One B-rep face of a CAD part: STEP entity #7966.
In plain terms, the planar face has unit normal (0, 0, -1).
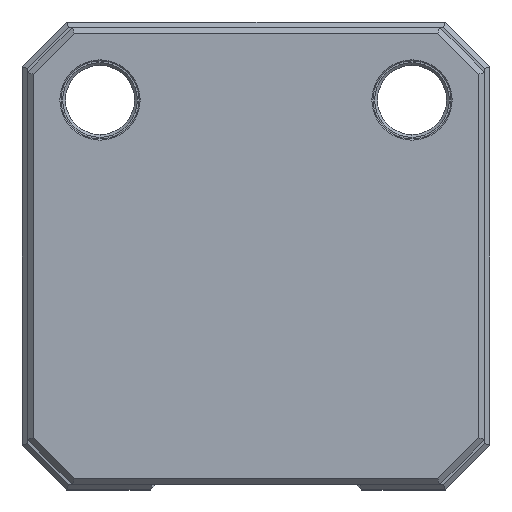
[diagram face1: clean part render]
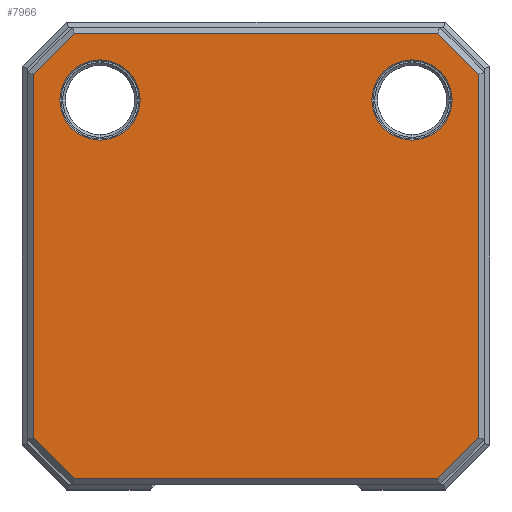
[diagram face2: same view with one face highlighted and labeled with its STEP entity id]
Its self-contained STEP definition (entity closure, numbers rounded to 3 decimals):
#1611 = EDGE_CURVE ( 'NONE', #13273, #13305, #17343, .T. ) ;
#1615 = EDGE_CURVE ( 'NONE', #13229, #13216, #7569, .T. ) ;
#1620 = EDGE_CURVE ( 'NONE', #13299, #13275, #17336, .T. ) ;
#1647 = EDGE_CURVE ( 'NONE', #13261, #13299, #17371, .T. ) ;
#1657 = EDGE_CURVE ( 'NONE', #13275, #13302, #17361, .T. ) ;
#1661 = EDGE_CURVE ( 'NONE', #13247, #13242, #7553, .T. ) ;
#1675 = EDGE_CURVE ( 'NONE', #13302, #13266, #17431, .T. ) ;
#1687 = EDGE_CURVE ( 'NONE', #13266, #13273, #17494, .T. ) ;
#1699 = EDGE_CURVE ( 'NONE', #13305, #13286, #17479, .T. ) ;
#1715 = EDGE_CURVE ( 'NONE', #13286, #13261, #17518, .T. ) ;
#1834 = EDGE_CURVE ( 'NONE', #13216, #13229, #7735, .T. ) ;
#1943 = EDGE_CURVE ( 'NONE', #13242, #13247, #7740, .T. ) ;
#4526 = AXIS2_PLACEMENT_3D ( 'NONE', #20304, #20255, #20301 ) ;
#6387 = EDGE_LOOP ( 'NONE', ( #19447, #19479 ) ) ;
#6462 = EDGE_LOOP ( 'NONE', ( #19484, #19480 ) ) ;
#6477 = EDGE_LOOP ( 'NONE', ( #19437, #19445, #19483, #19442, #19412, #19434, #19478, #19435 ) ) ;
#7536 = VECTOR ( 'NONE', #17348, 1000. ) ;
#7551 = AXIS2_PLACEMENT_3D ( 'NONE', #17341, #17324, #17302 ) ;
#7553 = CIRCLE ( 'NONE', #7590, 3.6 ) ;
#7559 = VECTOR ( 'NONE', #17478, 1000. ) ;
#7566 = VECTOR ( 'NONE', #17327, 1000. ) ;
#7567 = VECTOR ( 'NONE', #17393, 1000. ) ;
#7569 = CIRCLE ( 'NONE', #7551, 3.6 ) ;
#7587 = VECTOR ( 'NONE', #17413, 1000. ) ;
#7590 = AXIS2_PLACEMENT_3D ( 'NONE', #17448, #17414, #17443 ) ;
#7606 = VECTOR ( 'NONE', #17433, 1000. ) ;
#7643 = VECTOR ( 'NONE', #17539, 1000. ) ;
#7657 = VECTOR ( 'NONE', #17481, 1000. ) ;
#7680 = AXIS2_PLACEMENT_3D ( 'NONE', #17650, #17654, #17672 ) ;
#7735 = CIRCLE ( 'NONE', #7680, 3.6 ) ;
#7740 = CIRCLE ( 'NONE', #7769, 3.6 ) ;
#7769 = AXIS2_PLACEMENT_3D ( 'NONE', #16728, #16719, #16741 ) ;
#7966 = ADVANCED_FACE ( 'NONE', ( #20253, #20298, #20254 ), #20291, .F. ) ;
#13216 = VERTEX_POINT ( 'NONE', #20328 ) ;
#13229 = VERTEX_POINT ( 'NONE', #20346 ) ;
#13242 = VERTEX_POINT ( 'NONE', #20331 ) ;
#13247 = VERTEX_POINT ( 'NONE', #20313 ) ;
#13261 = VERTEX_POINT ( 'NONE', #20356 ) ;
#13266 = VERTEX_POINT ( 'NONE', #20388 ) ;
#13273 = VERTEX_POINT ( 'NONE', #20413 ) ;
#13275 = VERTEX_POINT ( 'NONE', #20369 ) ;
#13286 = VERTEX_POINT ( 'NONE', #20371 ) ;
#13299 = VERTEX_POINT ( 'NONE', #20412 ) ;
#13302 = VERTEX_POINT ( 'NONE', #20392 ) ;
#13305 = VERTEX_POINT ( 'NONE', #20405 ) ;
#16719 = DIRECTION ( 'NONE',  ( 0., 0., 1. ) ) ;
#16728 = CARTESIAN_POINT ( 'NONE',  ( -6.5, 6.5, 0. ) ) ;
#16741 = DIRECTION ( 'NONE',  ( 1., 0., 0. ) ) ;
#17302 = DIRECTION ( 'NONE',  ( 1., 0., 0. ) ) ;
#17303 = CARTESIAN_POINT ( 'NONE',  ( -40.5, 41., 0. ) ) ;
#17323 = CARTESIAN_POINT ( 'NONE',  ( -0.5, 41., 0. ) ) ;
#17324 = DIRECTION ( 'NONE',  ( 0., 0., 1. ) ) ;
#17327 = DIRECTION ( 'NONE',  ( 0., 1., 0. ) ) ;
#17336 = LINE ( 'NONE', #17303, #7566 ) ;
#17341 = CARTESIAN_POINT ( 'NONE',  ( -34.5, 6.5, 0. ) ) ;
#17343 = LINE ( 'NONE', #17323, #7536 ) ;
#17348 = DIRECTION ( 'NONE',  ( 0., -1., 0. ) ) ;
#17361 = LINE ( 'NONE', #17449, #7587 ) ;
#17371 = LINE ( 'NONE', #17372, #7567 ) ;
#17372 = CARTESIAN_POINT ( 'NONE',  ( -40.646, 4.354, 0. ) ) ;
#17393 = DIRECTION ( 'NONE',  ( -0.707, 0.707, 0. ) ) ;
#17413 = DIRECTION ( 'NONE',  ( 0.707, 0.707, 0. ) ) ;
#17414 = DIRECTION ( 'NONE',  ( 0., 0., 1. ) ) ;
#17431 = LINE ( 'NONE', #17432, #7606 ) ;
#17432 = CARTESIAN_POINT ( 'NONE',  ( 0., 40.5, 0. ) ) ;
#17433 = DIRECTION ( 'NONE',  ( 1., 0., 0. ) ) ;
#17443 = DIRECTION ( 'NONE',  ( 1., 0., 0. ) ) ;
#17448 = CARTESIAN_POINT ( 'NONE',  ( -6.5, 6.5, 0. ) ) ;
#17449 = CARTESIAN_POINT ( 'NONE',  ( -36.646, 40.646, 0. ) ) ;
#17478 = DIRECTION ( 'NONE',  ( 0.707, -0.707, 0. ) ) ;
#17479 = LINE ( 'NONE', #17497, #7657 ) ;
#17481 = DIRECTION ( 'NONE',  ( -0.707, -0.707, 0. ) ) ;
#17494 = LINE ( 'NONE', #17496, #7559 ) ;
#17496 = CARTESIAN_POINT ( 'NONE',  ( -0.354, 36.646, 0. ) ) ;
#17497 = CARTESIAN_POINT ( 'NONE',  ( -4.354, 0.354, 0. ) ) ;
#17518 = LINE ( 'NONE', #17530, #7643 ) ;
#17530 = CARTESIAN_POINT ( 'NONE',  ( 0., 0.5, 0. ) ) ;
#17539 = DIRECTION ( 'NONE',  ( -1., 0., 0. ) ) ;
#17650 = CARTESIAN_POINT ( 'NONE',  ( -34.5, 6.5, 0. ) ) ;
#17654 = DIRECTION ( 'NONE',  ( 0., 0., 1. ) ) ;
#17672 = DIRECTION ( 'NONE',  ( 1., 0., 0. ) ) ;
#19412 = ORIENTED_EDGE ( 'NONE', *, *, #1611, .T. ) ;
#19434 = ORIENTED_EDGE ( 'NONE', *, *, #1699, .T. ) ;
#19435 = ORIENTED_EDGE ( 'NONE', *, *, #1647, .T. ) ;
#19437 = ORIENTED_EDGE ( 'NONE', *, *, #1620, .T. ) ;
#19442 = ORIENTED_EDGE ( 'NONE', *, *, #1687, .T. ) ;
#19445 = ORIENTED_EDGE ( 'NONE', *, *, #1657, .T. ) ;
#19447 = ORIENTED_EDGE ( 'NONE', *, *, #1834, .T. ) ;
#19478 = ORIENTED_EDGE ( 'NONE', *, *, #1715, .T. ) ;
#19479 = ORIENTED_EDGE ( 'NONE', *, *, #1615, .T. ) ;
#19480 = ORIENTED_EDGE ( 'NONE', *, *, #1661, .T. ) ;
#19483 = ORIENTED_EDGE ( 'NONE', *, *, #1675, .T. ) ;
#19484 = ORIENTED_EDGE ( 'NONE', *, *, #1943, .T. ) ;
#20253 = FACE_BOUND ( 'NONE', #6462, .T. ) ;
#20254 = FACE_OUTER_BOUND ( 'NONE', #6477, .T. ) ;
#20255 = DIRECTION ( 'NONE',  ( 0., 0., 1. ) ) ;
#20291 = PLANE ( 'NONE',  #4526 ) ;
#20298 = FACE_BOUND ( 'NONE', #6387, .T. ) ;
#20301 = DIRECTION ( 'NONE',  ( 1., 0., 0. ) ) ;
#20304 = CARTESIAN_POINT ( 'NONE',  ( 0., 41., 0. ) ) ;
#20313 = CARTESIAN_POINT ( 'NONE',  ( -2.9, 6.5, 0. ) ) ;
#20328 = CARTESIAN_POINT ( 'NONE',  ( -38.1, 6.5, 0. ) ) ;
#20331 = CARTESIAN_POINT ( 'NONE',  ( -10.1, 6.5, 0. ) ) ;
#20346 = CARTESIAN_POINT ( 'NONE',  ( -30.9, 6.5, 0. ) ) ;
#20356 = CARTESIAN_POINT ( 'NONE',  ( -36.793, 0.5, 0. ) ) ;
#20369 = CARTESIAN_POINT ( 'NONE',  ( -40.5, 36.793, 0. ) ) ;
#20371 = CARTESIAN_POINT ( 'NONE',  ( -4.207, 0.5, 0. ) ) ;
#20388 = CARTESIAN_POINT ( 'NONE',  ( -4.207, 40.5, 0. ) ) ;
#20392 = CARTESIAN_POINT ( 'NONE',  ( -36.793, 40.5, 0. ) ) ;
#20405 = CARTESIAN_POINT ( 'NONE',  ( -0.5, 4.207, 0. ) ) ;
#20412 = CARTESIAN_POINT ( 'NONE',  ( -40.5, 4.207, 0. ) ) ;
#20413 = CARTESIAN_POINT ( 'NONE',  ( -0.5, 36.793, 0. ) ) ;
